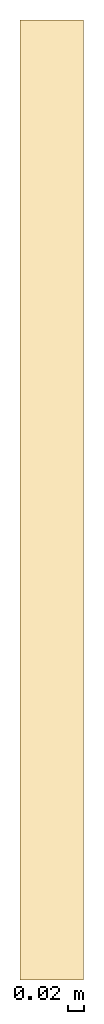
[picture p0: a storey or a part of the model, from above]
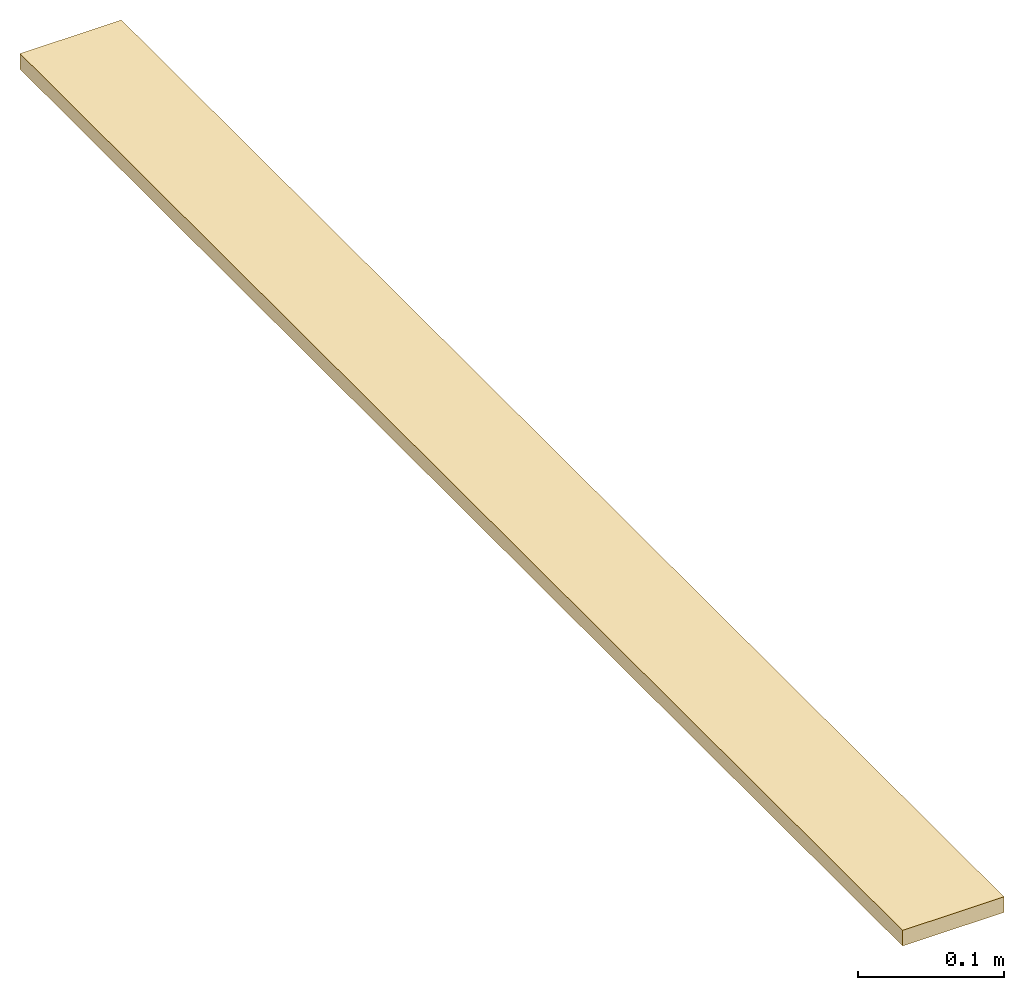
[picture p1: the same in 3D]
Properties of the parts of a building model (IFC4)

# File
Description: ViewDefinition [ReferenceView_V1.2], RevitIdentifiers [ContentGUID: d45b1106-0c7a-46e1-869b-c6a7bbcc7ea5, VersionGUID: 118b0530-1591-4ac2-8939-a10ffb714872, NumberOfSaves: 70], CoordinateReference [CoordinateBase: Internal Origin, ProjectSite: Internal], ExchangeRequirement [Architecture]
File name: 3dv__Detail__15__216, WS25 Wall, WS25_A_DE_21_VA_1 Copy 1.ifc
Time: 2025-12-19T14:29:25+01:00
Written by: ODA SDAI 25.12
Made in: Autodesk - Revit 26.3.0.37 (ENU) - 26.4.1.0

# IfcSite, Default
RefLatitude: 45, 45, 37, 23925; RefLongitude: 21, 14, 26, 780090; RefElevation: 0 cm

# IfcBuildingStorey (10)
Name | LongName | Elevation (cm)
B2__ABOVE Slab | B2__ABOVE Slab | -612
B1__ABOVE Slab | B1__ABOVE Slab | -312
L00__ABOVE Slab | L00__ABOVE Slab | -12
L01__ABOVE Slab | L01__ABOVE Slab | 273
L02__ABOVE Slab | L02__ABOVE Slab | 558
L03__ABOVE Slab | L03__ABOVE Slab | 843
L04__ABOVE Slab | L04__ABOVE Slab | 1128
L05__ABOVE Slab | L05__ABOVE Slab | 1413
L06__ABOVE Slab | L06__ABOVE Slab | 1698
L07__ABOVE Slab | L07__ABOVE Slab | 1983

# IfcCovering: Ceilings : Compound Ceiling : clg__EXT_Cladding
In: B1__ABOVE Slab
Type - PredefinedType: CEILING
Classification: A 6.1.2.1 Plafoane gips-carton, placi cu cerinte standard (Uniformat); Material: _STRUCTURE__Wood Solid, _FCD FINISH__Mineral Render__Combed, H L/O__Capatect Kreativeffekt "Filigrano"__White

# IfcSlab: Floors : Floor : flr__INT COVERING__Parquet
In: L00__ABOVE Slab
Type - PredefinedType: FLOOR; Material: _FINISH STAIR__Int__Parquet Flooring__Stairs, _FLR LAYERS__Screed, SL 0.5%__Semi-dry CEM, Rc ≥ 22.5 N/mm², _FLR COVERING__Polished Concrete, _FCD VENT LAYERS__Support Board__OSB 3
Classification: A 8.1.1.2 Pardoseli epoxidice si poliuretanice (Uniformat)

# IfcSlab: Floors : Floor : flr__STRUCTURE__Reinforced Concrete 25cm
In: L00__ABOVE Slab
Type - PredefinedType: FLOOR; Material: _STRUCTURE__Reinforced Concrete
Classification: S 1.2 Plansee si acoperisuri terasa (Uniformat)

# IfcWall: Columns : wll_s__TIMBER BLOCK__Triqbriq, Full Width__wp1 : WS25 2 (6)
In: L00__ABOVE Slab
Type - PredefinedType: SOLIDWALL; Material: Miscellaneous__Timber Block__Triqbriq, Y
Classification: A 1.0.1 (Uniformat)

# IfcWall: Columns : wll_s__TIMBER BLOCK__Triqbriq, Half Width__wp1 : WS25 2 (4)
In: L00__ABOVE Slab
Type - PredefinedType: SOLIDWALL; Material: Miscellaneous__Timber Block__Triqbriq, Y
Classification: A 1.0.1 (Uniformat)

# IfcWall: Walls : Basic Wall : wll__EXT ENCLOSURE__Spritzkork, Wood Insulation 6.4cm__TriqBriq, FS.1 2
In: L00__ABOVE Slab
Type - PredefinedType: STANDARD; Material: _FCD FINISH__Mineral Render__Combed, H L/O__Capatect Kreativeffekt "Filigrano"__White, _STRUCTURE__Wood Solid, _FCD LAYERS__Insulation__Wood-fiber__Steico
Classification: A 4.3.4.2.1 Pereti exteriori (Uniformat)

# IfcWall: Walls : Basic Wall : wll__EXT ENCLOSURE__Spritzkork, Wood Insulation 8.4cm__TriqBriq, FS.1 (2)
In: L00__ABOVE Slab
Type - PredefinedType: STANDARD; Material: _FCD FINISH__Mineral Render__Combed, H L/O__Capatect Kreativeffekt "Filigrano"__White, _STRUCTURE__Wood Solid, _FCD LAYERS__Insulation__Wood-fiber__Steico
Classification: A 4.3.4.2.1 Pereti exteriori (Uniformat)

# IfcWall: Walls : Basic Wall : wll__INT FINISH__Spritzkork, Lime - CEM Plaster 2.4cm TRIQBRIQ
In: L00__ABOVE Slab
Type - PredefinedType: STANDARD; Material: _WLL & CLG FINISHES__Lime - CEM Plaster, _FCD LAYERS__Insulation__EPS 120__Austrotherm EPS A120
Classification: A 7.1.1 Tencuieli umede (Uniformat)

# IfcWall: Walls : Basic Wall : wll__STRUCTURE__Reinforced Concrete 15cm
In: L00__ABOVE Slab
Type - PredefinedType: STANDARD
Classification: S 2.1 Pereti portanti (Uniformat); Material: _STRUCTURE__Reinforced Concrete

# IfcWall: Walls : Basic Wall : wll__WP & INSULATION_1cm
In: L00__ABOVE Slab
Type - PredefinedType: STANDARD; Material: _FND LAYERS__Insulation__Foam Glass__Glapor
Classification: A 2.1.1 Sisteme termohidroizolante - suprafete verticale fundatii (Uniformat)
